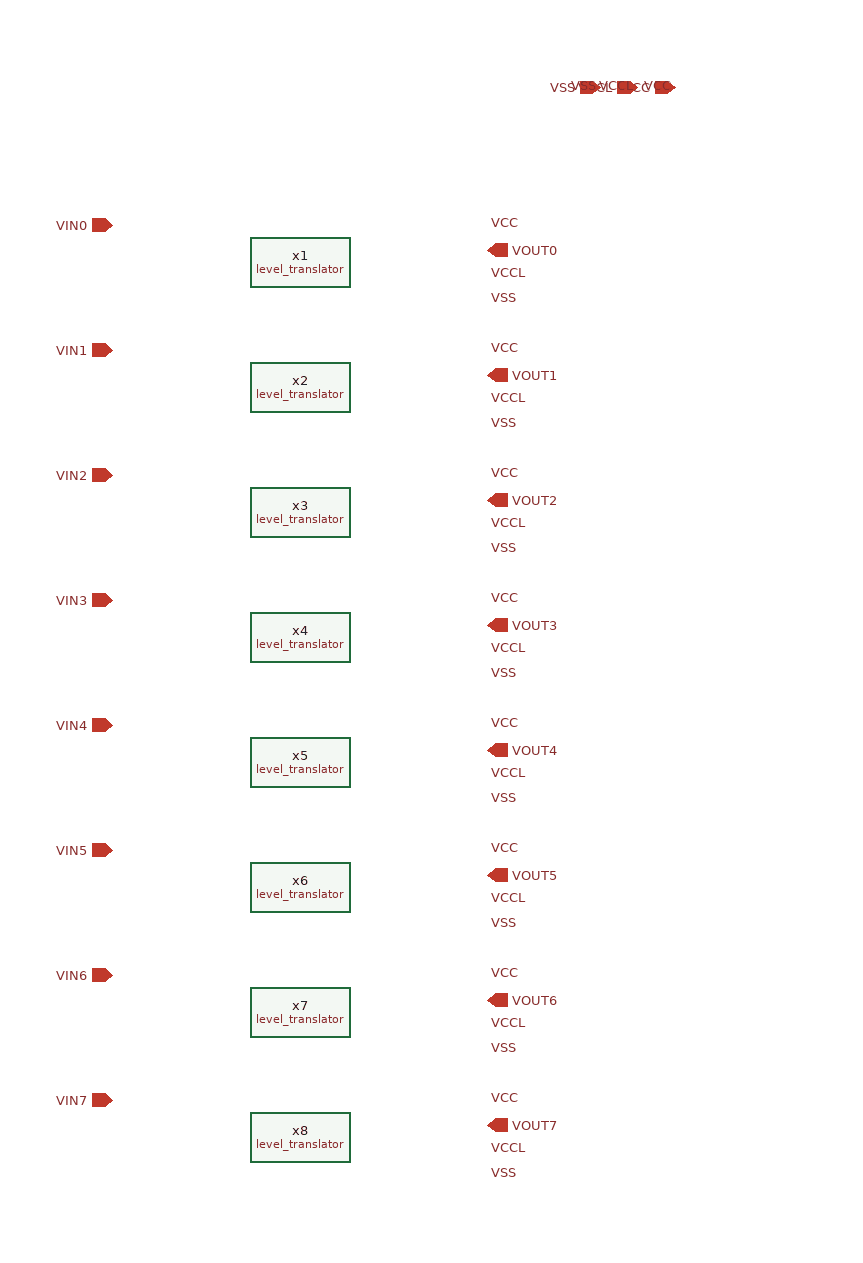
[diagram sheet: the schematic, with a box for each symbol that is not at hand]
v {xschem version=3.4.0 file_version=1.2
}
G {}
K {}
V {}
S {}
E {}
C {devices/iopin.sym} 430 -100 3 0 {name=p1 lab=VCC}
C {devices/iopin.sym} 400 -100 3 0 {name=p5 lab=VCCL}
C {devices/iopin.sym} 370 -100 3 0 {name=p6 lab=VSS}
C {devices/ipin.sym} -20 10 0 0 {name=p2 lab=VIN0}
C {devices/opin.sym} 280 30 0 0 {name=p3 lab=VOUT0}
C {devices/lab_pin.sym} 280 70 0 1 {name=p4 sig_type=std_logic lab=VSS}
C {devices/lab_pin.sym} 280 10 0 1 {name=p7 sig_type=std_logic lab=VCC}
C {devices/lab_pin.sym} 280 50 0 1 {name=p8 sig_type=std_logic lab=VCCL}
C {devices/lab_pin.sym} 370 -100 3 0 {name=p9 sig_type=std_logic lab=VSS}
C {devices/lab_pin.sym} 430 -100 3 0 {name=p10 sig_type=std_logic lab=VCC}
C {devices/lab_pin.sym} 400 -100 3 0 {name=p11 sig_type=std_logic lab=VCCL}
C {devices/lab_pin.sym} 280 170 0 1 {name=p12 sig_type=std_logic lab=VSS}
C {devices/lab_pin.sym} 280 270 0 1 {name=p13 sig_type=std_logic lab=VSS}
C {devices/lab_pin.sym} 280 370 0 1 {name=p14 sig_type=std_logic lab=VSS}
C {devices/lab_pin.sym} 280 470 0 1 {name=p15 sig_type=std_logic lab=VSS}
C {devices/lab_pin.sym} 280 570 0 1 {name=p16 sig_type=std_logic lab=VSS}
C {devices/lab_pin.sym} 280 670 0 1 {name=p17 sig_type=std_logic lab=VSS}
C {devices/lab_pin.sym} 280 770 0 1 {name=p18 sig_type=std_logic lab=VSS}
C {devices/lab_pin.sym} 280 110 0 1 {name=p19 sig_type=std_logic lab=VCC}
C {devices/lab_pin.sym} 280 150 0 1 {name=p20 sig_type=std_logic lab=VCCL}
C {devices/lab_pin.sym} 280 210 0 1 {name=p21 sig_type=std_logic lab=VCC}
C {devices/lab_pin.sym} 280 250 0 1 {name=p22 sig_type=std_logic lab=VCCL}
C {devices/lab_pin.sym} 280 310 0 1 {name=p25 sig_type=std_logic lab=VCC}
C {devices/lab_pin.sym} 280 350 0 1 {name=p26 sig_type=std_logic lab=VCCL}
C {devices/lab_pin.sym} 280 410 0 1 {name=p27 sig_type=std_logic lab=VCC}
C {devices/lab_pin.sym} 280 450 0 1 {name=p28 sig_type=std_logic lab=VCCL}
C {devices/lab_pin.sym} 280 510 0 1 {name=p29 sig_type=std_logic lab=VCC}
C {devices/lab_pin.sym} 280 550 0 1 {name=p30 sig_type=std_logic lab=VCCL}
C {devices/lab_pin.sym} 280 610 0 1 {name=p31 sig_type=std_logic lab=VCC}
C {devices/lab_pin.sym} 280 650 0 1 {name=p32 sig_type=std_logic lab=VCCL}
C {devices/lab_pin.sym} 280 710 0 1 {name=p33 sig_type=std_logic lab=VCC}
C {devices/lab_pin.sym} 280 750 0 1 {name=p34 sig_type=std_logic lab=VCCL}
C {devices/ipin.sym} -20 110 0 0 {name=p35 lab=VIN1}
C {devices/ipin.sym} -20 210 0 0 {name=p36 lab=VIN2}
C {devices/ipin.sym} -20 310 0 0 {name=p37 lab=VIN3}
C {devices/ipin.sym} -20 410 0 0 {name=p38 lab=VIN4}
C {devices/ipin.sym} -20 510 0 0 {name=p39 lab=VIN5}
C {devices/ipin.sym} -20 610 0 0 {name=p40 lab=VIN6}
C {devices/ipin.sym} -20 710 0 0 {name=p41 lab=VIN7}
C {devices/opin.sym} 280 130 0 0 {name=p23 lab=VOUT1}
C {devices/opin.sym} 280 230 0 0 {name=p24 lab=VOUT2}
C {devices/opin.sym} 280 330 0 0 {name=p42 lab=VOUT3}
C {devices/opin.sym} 280 430 0 0 {name=p43 lab=VOUT4}
C {devices/opin.sym} 280 530 0 0 {name=p44 lab=VOUT5}
C {devices/opin.sym} 280 630 0 0 {name=p45 lab=VOUT6}
C {devices/opin.sym} 280 730 0 0 {name=p46 lab=VOUT7}
C {/foss/designs/8_bit_dac/Level_translator/level_translator.sym} 130 40 0 0 {name=x1}
C {/foss/designs/8_bit_dac/Level_translator/level_translator.sym} 130 140 0 0 {name=x2}
C {/foss/designs/8_bit_dac/Level_translator/level_translator.sym} 130 240 0 0 {name=x3}
C {/foss/designs/8_bit_dac/Level_translator/level_translator.sym} 130 340 0 0 {name=x4}
C {/foss/designs/8_bit_dac/Level_translator/level_translator.sym} 130 440 0 0 {name=x5}
C {/foss/designs/8_bit_dac/Level_translator/level_translator.sym} 130 540 0 0 {name=x6}
C {/foss/designs/8_bit_dac/Level_translator/level_translator.sym} 130 640 0 0 {name=x7}
C {/foss/designs/8_bit_dac/Level_translator/level_translator.sym} 130 740 0 0 {name=x8}
